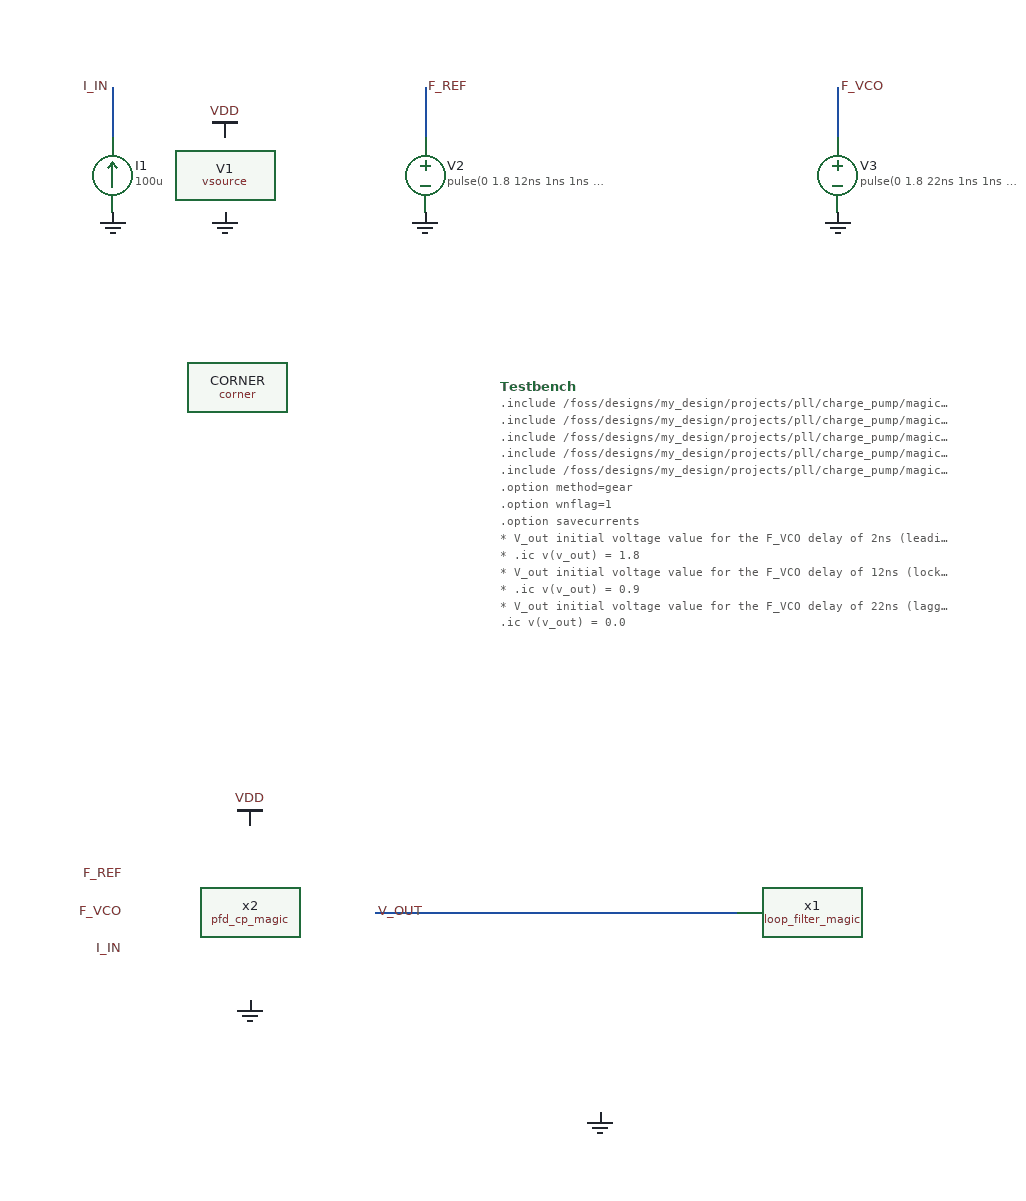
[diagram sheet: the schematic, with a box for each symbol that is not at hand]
v {xschem version=3.4.6 file_version=1.2}
G {}
K {}
V {}
S {}
E {}
B 2 1950 -5830 3310 -5170 {flags=graph
y1=0
y2=1.8
ypos1=0
ypos2=2
divy=5
subdivy=1
unity=1
x1=2.1280357e-07
x2=2.1414051e-07
divx=5
subdivx=1
xlabmag=1.0
ylabmag=1.0


dataset=-1
unitx=1
logx=0
logy=0








linewidth_mult=3







autoload=0
sim_type=tran
color="6 7"
node="f_ref
f_vco"}
B 2 1950 -4440 3330 -3760 {flags=graph
y1=0
y2=0.01
ypos1=0
ypos2=2
divy=5
subdivy=1
unity=1
x1=2.1280357e-07
x2=2.1414051e-07
divx=5
subdivx=1
xlabmag=1.0
ylabmag=1.0


dataset=-1
unitx=1
logx=0
logy=0








linewidth_mult=5





color="6 5"
node="up_pfd_b
down_pfd_b"}
B 2 1950 -5150 3330 -4450 {flags=graph
y1=0.0015141901
y2=0.0079141901
ypos1=0
ypos2=2
divy=5
subdivy=1
unity=1
x1=2.1280357e-07
x2=2.1414051e-07
divx=5
subdivx=1
xlabmag=1.0
ylabmag=1.0


dataset=-1
unitx=1
logx=0
logy=0








linewidth_mult=5

color="6 5"
node="up_pfd
down_pfd"}
B 2 1950 -3740 3330 -3060 {flags=graph
y1=0.002
y2=0.012
ypos1=0
ypos2=2
divy=5
subdivy=1
unity=1
x1=2.1280357e-07
x2=2.1414051e-07
divx=5
subdivx=1
xlabmag=1.0
ylabmag=1.0


dataset=-1
unitx=1
logx=0
logy=0








linewidth_mult=5





color="6 5"
node="up
down_b"}
B 2 1950 -3040 3330 -2360 {flags=graph
y1=0.3664
y2=2.2834
ypos1=0
ypos2=2
divy=5
subdivy=1
unity=1
x1=2.1280357e-07
x2=2.1414051e-07
divx=5
subdivx=1
xlabmag=1.0
ylabmag=1.0


dataset=-1
unitx=1
logx=0
logy=0








linewidth_mult=5





color="6 5"
node="up_b
down"}
B 2 1960 -2320 3340 -1640 {flags=graph
y1=-0.13
y2=1.9
ypos1=0
ypos2=2
divy=5
subdivy=1
unity=1
x1=2.1280357e-07
x2=2.1414051e-07
divx=5
subdivx=1
xlabmag=1.0
ylabmag=1.0


dataset=-1
unitx=1
logx=0
logy=0








linewidth_mult=5





color="6 5"
node="up_input
down_input"}
B 2 400 -4440 1760 -3770 {flags=graph
y1=0.89
y2=0.91
ypos1=0
ypos2=2
divy=5
subdivy=1
unity=1
x1=2.1280357e-07
x2=2.1414051e-07
divx=5
subdivx=1
xlabmag=1.0
ylabmag=1.0


dataset=-1
unitx=1
logx=0
logy=0








linewidth_mult=7






color=5
node=v_out}
B 2 1960 -1540 3320 -870 {flags=graph
y1=3.9e-28
y2=7e-07
ypos1=0
ypos2=2
divy=5
subdivy=1
unity=1
x1=2.1280357e-07
x2=2.1414051e-07
divx=5
subdivx=1
xlabmag=1.0
ylabmag=1.0


dataset=-1
unitx=1
logx=0
logy=0








linewidth_mult=7










color="6 7 6 7 6"
node="i(@m.x2.x5.msky130_fd_pr__nfet_01v8[id])
i(@m.x2.x4.msky130_fd_pr__pfet_01v8[id])
i(@m.x2.x3.msky130_fd_pr__nfet_01v8[id])
i(@m.x2.x2.msky130_fd_pr__pfet_01v8[id])
i(@m.x2.x1.msky130_fd_pr__nfet_01v8[id])"}
B 2 1960 -840 3320 -170 {flags=graph
y1=7.5e-25
y2=1.7e-18
ypos1=0
ypos2=2
divy=5
subdivy=1
unity=1
x1=2.1280357e-07
x2=2.1414051e-07
divx=5
subdivx=1
xlabmag=1.0
ylabmag=1.0


dataset=-1
unitx=1
logx=0
logy=0








linewidth_mult=7










color=6
node=i(@m.x2.x1.msky130_fd_pr__nfet_01v8[id])}
B 2 400 -3740 1760 -3070 {flags=graph
y1=0
y2=0.00032
ypos1=0
ypos2=2
divy=5
subdivy=1
unity=1
x1=2.1280357e-07
x2=2.1414051e-07
divx=5
subdivx=1
xlabmag=1.0
ylabmag=1.0


dataset=-1
unitx=1
logx=0
logy=0








linewidth_mult=7







color="7 7 7 7 7 7 7 7 7 7 7 7 7 7 7 7 7 7 7 7 7 7 7 7 7 7 7 7 7 7 7 7 7 7 7 7 7 7 7 7 7 7 7 7 7 7 7 7 7 7 7 7 7 7 7 7 7 7 7 7 7 7 7 7 7 7 7 7 7 7 7 7 7 7 7 7 7 7 7 7 7 7 7 7 7 7 7 7 7 7 7 7 7 7 7 7 7 7 7 7 7 7 7 7 7 7 7 7 7 7 7 7 7 7 7 7 7 7 7 7 7 7 7 7 7 7 7 7 7 7 7 7 7 7 7 7 7 7 7 7 7 7 7 7"
node="i(@m.x2.x150.msky130_fd_pr__pfet_01v8[id])
i(@m.x2.x149.msky130_fd_pr__nfet_01v8[id])
i(@m.x2.x148.msky130_fd_pr__pfet_01v8[id])
i(@m.x2.x147.msky130_fd_pr__nfet_01v8[id])
i(@m.x2.x146.msky130_fd_pr__pfet_01v8[id])
i(@m.x2.x145.msky130_fd_pr__nfet_01v8[id])
i(@m.x2.x144.msky130_fd_pr__nfet_01v8[id])
i(@m.x2.x143.msky130_fd_pr__nfet_01v8[id])
i(@m.x2.x142.msky130_fd_pr__pfet_01v8[id])
i(@m.x2.x141.msky130_fd_pr__nfet_01v8[id])
i(@m.x2.x140.msky130_fd_pr__pfet_01v8[id])
i(@m.x2.x139.msky130_fd_pr__pfet_01v8[id])
i(@m.x2.x138.msky130_fd_pr__nfet_01v8[id])
i(@m.x2.x136.msky130_fd_pr__pfet_01v8[id])
i(@m.x2.x135.msky130_fd_pr__nfet_01v8[id])
i(@m.x2.x134.msky130_fd_pr__pfet_01v8[id])
i(@m.x2.x133.msky130_fd_pr__nfet_01v8[id])
i(@m.x2.x132.msky130_fd_pr__nfet_01v8[id])
i(@m.x2.x131.msky130_fd_pr__nfet_01v8[id])
i(@m.x2.x130.msky130_fd_pr__pfet_01v8[id])
i(@m.x2.x129.msky130_fd_pr__pfet_01v8[id])
i(@m.x2.x128.msky130_fd_pr__nfet_01v8[id])
i(@m.x2.x127.msky130_fd_pr__pfet_01v8[id])
i(@m.x2.x126.msky130_fd_pr__pfet_01v8[id])
i(@m.x2.x125.msky130_fd_pr__pfet_01v8[id])
i(@m.x2.x124.msky130_fd_pr__nfet_01v8[id])
i(@m.x2.x123.msky130_fd_pr__pfet_01v8[id])
i(@m.x2.x122.msky130_fd_pr__pfet_01v8[id])
i(@m.x2.x121.msky130_fd_pr__pfet_01v8[id])
i(@m.x2.x120.msky130_fd_pr__nfet_01v8[id])
i(@m.x2.x119.msky130_fd_pr__pfet_01v8[id])
i(@m.x2.x118.msky130_fd_pr__pfet_01v8[id])
i(@m.x2.x117.msky130_fd_pr__nfet_01v8[id])
i(@m.x2.x116.msky130_fd_pr__nfet_01v8[id])
i(@m.x2.x115.msky130_fd_pr__nfet_01v8[id])
i(@m.x2.x114.msky130_fd_pr__nfet_01v8[id])
i(@m.x2.x113.msky130_fd_pr__nfet_01v8[id])
i(@m.x2.x112.msky130_fd_pr__pfet_01v8[id])
i(@m.x2.x111.msky130_fd_pr__nfet_01v8[id])
i(@m.x2.x110.msky130_fd_pr__pfet_01v8[id])
i(@m.x2.x108.msky130_fd_pr__pfet_01v8[id])
i(@m.x2.x107.msky130_fd_pr__pfet_01v8[id])
i(@m.x2.x106.msky130_fd_pr__pfet_01v8[id])
i(@m.x2.x105.msky130_fd_pr__nfet_01v8[id])
i(@m.x2.x104.msky130_fd_pr__nfet_01v8[id])
i(@m.x2.x103.msky130_fd_pr__nfet_01v8[id])
i(@m.x2.x102.msky130_fd_pr__pfet_01v8[id])
i(@m.x2.x100.msky130_fd_pr__pfet_01v8[id])
i(@m.x2.x99.msky130_fd_pr__pfet_01v8[id])
i(@m.x2.x97.msky130_fd_pr__nfet_01v8[id])
i(@m.x2.x96.msky130_fd_pr__nfet_01v8[id])
i(@m.x2.x95.msky130_fd_pr__pfet_01v8[id])
i(@m.x2.x94.msky130_fd_pr__pfet_01v8[id])
i(@m.x2.x93.msky130_fd_pr__nfet_01v8[id])
i(@m.x2.x92.msky130_fd_pr__nfet_01v8[id])
i(@m.x2.x91.msky130_fd_pr__nfet_01v8[id])
i(@m.x2.x90.msky130_fd_pr__nfet_01v8[id])
i(@m.x2.x88.msky130_fd_pr__nfet_01v8[id])
i(@m.x2.x87.msky130_fd_pr__nfet_01v8[id])
i(@m.x2.x86.msky130_fd_pr__pfet_01v8[id])
i(@m.x2.x85.msky130_fd_pr__nfet_01v8[id])
i(@m.x2.x84.msky130_fd_pr__pfet_01v8[id])
i(@m.x2.x83.msky130_fd_pr__nfet_01v8[id])
i(@m.x2.x82.msky130_fd_pr__pfet_01v8[id])
i(@m.x2.x81.msky130_fd_pr__nfet_01v8[id])
i(@m.x2.x79.msky130_fd_pr__nfet_01v8[id])
i(@m.x2.x78.msky130_fd_pr__nfet_01v8[id])
i(@m.x2.x77.msky130_fd_pr__nfet_01v8[id])
i(@m.x2.x76.msky130_fd_pr__nfet_01v8[id])
i(@m.x2.x75.msky130_fd_pr__pfet_01v8[id])
i(@m.x2.x74.msky130_fd_pr__nfet_01v8[id])
i(@m.x2.x73.msky130_fd_pr__pfet_01v8[id])
i(@m.x2.x72.msky130_fd_pr__pfet_01v8[id])
i(@m.x2.x71.msky130_fd_pr__pfet_01v8[id])
i(@m.x2.x70.msky130_fd_pr__pfet_01v8[id])
i(@m.x2.x69.msky130_fd_pr__pfet_01v8[id])
i(@m.x2.x68.msky130_fd_pr__nfet_01v8[id])
i(@m.x2.x67.msky130_fd_pr__pfet_01v8[id])
i(@m.x2.x66.msky130_fd_pr__nfet_01v8[id])
i(@m.x2.x65.msky130_fd_pr__pfet_01v8[id])
i(@m.x2.x64.msky130_fd_pr__nfet_01v8[id])
i(@m.x2.x63.msky130_fd_pr__pfet_01v8[id])
i(@m.x2.x62.msky130_fd_pr__pfet_01v8[id])
i(@m.x2.x61.msky130_fd_pr__pfet_01v8[id])
i(@m.x2.x60.msky130_fd_pr__nfet_01v8[id])
i(@m.x2.x59.msky130_fd_pr__pfet_01v8[id])
i(@m.x2.x58.msky130_fd_pr__pfet_01v8[id])
i(@m.x2.x57.msky130_fd_pr__nfet_01v8[id])
i(@m.x2.x56.msky130_fd_pr__nfet_01v8[id])
i(@m.x2.x55.msky130_fd_pr__pfet_01v8[id])
i(@m.x2.x54.msky130_fd_pr__pfet_01v8[id])
i(@m.x2.x53.msky130_fd_pr__pfet_01v8[id])
i(@m.x2.x52.msky130_fd_pr__pfet_01v8[id])
i(@m.x2.x51.msky130_fd_pr__nfet_01v8[id])
i(@m.x2.x50.msky130_fd_pr__pfet_01v8[id])
i(@m.x2.x49.msky130_fd_pr__nfet_01v8[id])
i(@m.x2.x48.msky130_fd_pr__pfet_01v8[id])
i(@m.x2.x47.msky130_fd_pr__nfet_01v8[id])
i(@m.x2.x46.msky130_fd_pr__nfet_01v8[id])
i(@m.x2.x45.msky130_fd_pr__pfet_01v8[id])
i(@m.x2.x44.msky130_fd_pr__pfet_01v8[id])
i(@m.x2.x43.msky130_fd_pr__nfet_01v8[id])
i(@m.x2.x42.msky130_fd_pr__pfet_01v8[id])
i(@m.x2.x41.msky130_fd_pr__pfet_01v8[id])
i(@m.x2.x40.msky130_fd_pr__pfet_01v8[id])
i(@m.x2.x39.msky130_fd_pr__nfet_01v8[id])
i(@m.x2.x38.msky130_fd_pr__nfet_01v8[id])
i(@m.x2.x37.msky130_fd_pr__nfet_01v8[id])
i(@m.x2.x36.msky130_fd_pr__nfet_01v8[id])
i(@m.x2.x35.msky130_fd_pr__nfet_01v8[id])
i(@m.x2.x34.msky130_fd_pr__nfet_01v8[id])
i(@m.x2.x33.msky130_fd_pr__pfet_01v8[id])
i(@m.x2.x32.msky130_fd_pr__pfet_01v8[id])
i(@m.x2.x31.msky130_fd_pr__pfet_01v8[id])
i(@m.x2.x30.msky130_fd_pr__pfet_01v8[id])
i(@m.x2.x29.msky130_fd_pr__nfet_01v8[id])
i(@m.x2.x27.msky130_fd_pr__nfet_01v8[id])
i(@m.x2.x26.msky130_fd_pr__nfet_01v8[id])
i(@m.x2.x25.msky130_fd_pr__pfet_01v8[id])
i(@m.x2.x24.msky130_fd_pr__nfet_01v8[id])
i(@m.x2.x23.msky130_fd_pr__nfet_01v8[id])
i(@m.x2.x22.msky130_fd_pr__pfet_01v8[id])
i(@m.x2.x21.msky130_fd_pr__pfet_01v8[id])
i(@m.x2.x20.msky130_fd_pr__nfet_01v8[id])
i(@m.x2.x19.msky130_fd_pr__nfet_01v8[id])
i(@m.x2.x18.msky130_fd_pr__nfet_01v8[id])
i(@m.x2.x17.msky130_fd_pr__pfet_01v8[id])
i(@m.x2.x16.msky130_fd_pr__nfet_01v8[id])
i(@m.x2.x15.msky130_fd_pr__nfet_01v8[id])
i(@m.x2.x14.msky130_fd_pr__nfet_01v8[id])
i(@m.x2.x13.msky130_fd_pr__pfet_01v8[id])
i(@m.x2.x12.msky130_fd_pr__pfet_01v8[id])
i(@m.x2.x11.msky130_fd_pr__pfet_01v8[id])
i(@m.x2.x10.msky130_fd_pr__pfet_01v8[id])
i(@m.x2.x9.msky130_fd_pr__pfet_01v8[id])
i(@m.x2.x8.msky130_fd_pr__pfet_01v8[id])
i(@m.x2.x7.msky130_fd_pr__nfet_01v8[id])
i(@m.x2.x6.msky130_fd_pr__pfet_01v8[id])
i(@m.x2.x5.msky130_fd_pr__nfet_01v8[id])
i(@m.x2.x4.msky130_fd_pr__nfet_01v8[id])
i(@m.x2.x3.msky130_fd_pr__nfet_01v8[id])
i(@m.x2.x2.msky130_fd_pr__pfet_01v8[id])
i(@m.x2.x1.msky130_fd_pr__pfet_01v8[id])
i(@m.x2.x0.msky130_fd_pr__nfet_01v8[id])"}
B 2 400 -3010 1760 -2340 {flags=graph
y1=3.4e-18
y2=0.00012
ypos1=0
ypos2=2
divy=5
subdivy=1
unity=1
x1=2.1280357e-07
x2=2.1414051e-07
divx=5
subdivx=1
xlabmag=1.0
ylabmag=1.0


dataset=-1
unitx=1
logx=0
logy=0








linewidth_mult=5








color=6
node="\\"i(@m.x2.x10.msky130_fd_pr__pfet_01v8[id]) i(@m.x2.x73.msky130_fd_pr__pfet_01v8[id]) i(@m.x2.x130.msky130_fd_pr__pfet_01v8[id]) i(@m.x2.x146.msky130_fd_pr__pfet_01v8[id]) + + + \\""}
B 2 400 -2280 1760 -1610 {flags=graph
y1=1.2e-14
y2=0.00012
ypos1=0
ypos2=2
divy=5
subdivy=1
unity=1
x1=2.1280357e-07
x2=2.1414051e-07
divx=5
subdivx=1
xlabmag=1.0
ylabmag=1.0


dataset=-1
unitx=1
logx=0
logy=0








linewidth_mult=4








color=7
node="\\"i(@m.x2.x76.msky130_fd_pr__nfet_01v8[id]) i(@m.x2.x105.msky130_fd_pr__nfet_01v8[id]) + \\""}
B 2 400 -1570 1760 -900 {flags=graph
y1=3.5e-18
y2=0.00012
ypos1=0
ypos2=2
divy=5
subdivy=1
unity=1
x1=2.1280357e-07
x2=2.1414051e-07
divx=5
subdivx=1
xlabmag=1.0
ylabmag=1.0


dataset=-1
unitx=1
logx=0
logy=0








linewidth_mult=5








color="6 7"
node="\\"i(@m.x2.x10.msky130_fd_pr__pfet_01v8[id]) i(@m.x2.x73.msky130_fd_pr__pfet_01v8[id]) i(@m.x2.x130.msky130_fd_pr__pfet_01v8[id]) i(@m.x2.x146.msky130_fd_pr__pfet_01v8[id]) + + + \\"
\\"i(@m.x2.x76.msky130_fd_pr__nfet_01v8[id]) i(@m.x2.x105.msky130_fd_pr__nfet_01v8[id]) + \\""}
N 1040 -5570 1040 -5530 {
lab=F_REF}
N 1370 -5570 1370 -5530 {
lab=F_VCO}
N 790 -5570 790 -5530 {
lab=I_IN}
N 1000 -4910 1290 -4910 {lab=V_OUT}
C {sky130_fd_pr/corner.sym} 890 -5330 0 0 {name=CORNER only_toplevel=false corner=tt}
C {devices/code.sym} 1100 -5331.25 0 0 {name=Testbench only_toplevel=false value="

.include /foss/designs/my_design/projects/pll/charge_pump/magic/pfd_cp_magic.spice
.include /foss/designs/my_design/projects/pll/charge_pump/magic/pfd_cp_input_magic.spice
.include /foss/designs/my_design/projects/pll/charge_pump/magic/charge_pump_magic.spice
.include /foss/designs/my_design/projects/pll/charge_pump/magic/rail_to_rail_opamp_magic.spice
.include /foss/designs/my_design/projects/pll/charge_pump/magic/loop_filter_magic.spice

.option method=gear
.option wnflag=1
.option savecurrents

* V_out initial voltage value for the F_VCO delay of 2ns  (leading)
* .ic v(v_out) = 1.8

* V_out initial voltage value for the F_VCO delay of 12ns (lock condition)
* .ic v(v_out) = 0.9

* V_out initial voltage value for the F_VCO delay of 22ns (lagging)
.ic v(v_out) = 0.0

.control
  save v(f_ref) save v(f_vco) save v(i_in) save v(up_pfd) v(down_pfd) v(up_pfd_b) v(down_pfd_b) v(up) v(up_b) v(down) v(down_b) v(x) v(opamp_out) v(up_input) v(down_input) v(down_gate) v(v_out)
  * save all

  * timestep for exact simulation results
  * tran 5ps 0.5us

  * timestep for faster simulation results
  tran 50ps 0.5us

  remzerovec
  write pfd_charge_pump_magic_3.raw
  set appendwrite

.endc

"
}
C {devices/vsource.sym} 880 -5500 0 0 {name=V1 value=1.8 savecurrent=false}
C {devices/gnd.sym} 880 -5470 0 0 {name=l2 lab=GND}
C {devices/vdd.sym} 880 -5530 0 1 {name=l3 lab=VDD}
C {devices/vsource.sym} 1040 -5500 0 0 {name=V2 value=pulse"(0 1.8 12ns 1ns 1ns 24ns 50ns)" savecurrent=false
* }
C {devices/gnd.sym} 1040 -5470 0 0 {name=l10 lab=GND}
C {devices/lab_pin.sym} 1040 -5570 0 1 {name=p11 sig_type=std_logic lab=F_REF}
C {devices/vsource.sym} 1370 -5500 0 0 {name=V3 value="pulse(0 1.8 22ns 1ns 1ns 24ns 50ns)" savecurrent=false}
C {devices/gnd.sym} 1370 -5470 0 0 {name=l15 lab=GND}
C {devices/lab_pin.sym} 1370 -5570 0 1 {name=p12 sig_type=std_logic lab=F_VCO}
C {devices/isource.sym} 790 -5500 2 0 {name=I1 value=100u}
C {devices/gnd.sym} 790 -5470 0 0 {name=l26 lab=GND}
C {devices/lab_pin.sym} 790 -5570 2 1 {name=p3 sig_type=std_logic lab=I_IN}
C {devices/vdd.sym} 900 -4980 0 1 {name=l32 lab=VDD
value="

.include /foss/pdks/sky130A/libs.ref/sky130_fd_sc_hd/spice/sky130_fd_sc_hd.spice

.option method=gear
.option wnflag=1

* V_out initial voltage value for the F_VCO delay of 2ns  (leading)
* .ic v(vout) = 1.8

* V_out initial voltage value for the F_VCO delay of 12ns (lock condition)
.ic v(vout) = 0.83

* V_out initial voltage value for the F_VCO delay of 22ns (lagging)
* .ic v(vout) = 0

.control
  save v(f_ref) save v(f_vco) save v(i_in) save v(up_pfd) v(down_pfd) v(up_pfd_b) v(down_pfd_b) v(up) v(up_b) v(down) v(down_b) v(x) v(opamp_out) v(up_input) v(down_input) v(down_gate) v(vout)

  * timestep for exact simulation results
  * tran 5ps 0.5us

  * timestep for faster simulation results
  tran 50ps 0.5us

  remzerovec
  write pfd_charge_pump_10.raw
  set appendwrite

.endc

"


v(vout)="0.0

.control
  save all

  * timestep for exact simulation results
  tran 5ps 0.5us

  * timestep for faster simulation results
  * tran 50ps 0.5us

  remzerovec
  write pfd_charge_pump_10.raw
  set appendA}
C {devices/gnd.sym} 900 -4840 0 0 {name=l33 lab=GND
value="

.include /foss/pdks/sky130A/libs.ref/sky130_fd_sc_hd/spice/sky130_fd_sc_hd.spice

.option method=gear
.option wnflag=1

* V_out initial voltage value for the F_VCO delay of 2ns  (leading)
* .ic v(vout) = 1.8

* V_out initial voltage value for the F_VCO delay of 12ns (lock condition)
.ic v(vout) = 0.83

* V_out initial voltage value for the F_VCO delay of 22ns (lagging)
* .ic v(vout) = 0

.control
  save v(f_ref) save v(f_vco) save v(i_in) save v(up_pfd) v(down_pfd) v(up_pfd_b) v(down_pfd_b) v(up) v(up_b) v(down) v(down_b) v(x) v(opamp_out) v(up_input) v(down_input) v(down_gate) v(vout)

  * timestep for exact simulation results
  * tran 5ps 0.5us

  * timestep for faster simulation results
  tran 50ps 0.5us

  remzerovec
  write pfd_charge_pump_10.raw
  set appendwrite

.endc

"}
C {devices/gnd.sym} 1180 -4750 0 0 {name=l1 lab=GND
value="

.include /foss/pdks/sky130A/libs.ref/sky130_fd_sc_hd/spice/sky130_fd_sc_hd.spice

.option method=gear
.option wnflag=1

* V_out initial voltage value for the F_VCO delay of 2ns  (leading)
* .ic v(vout) = 1.8

* V_out initial voltage value for the F_VCO delay of 12ns (lock condition)
.ic v(vout) = 0.83

* V_out initial voltage value for the F_VCO delay of 22ns (lagging)
* .ic v(vout) = 0

.control
  save v(f_ref) save v(f_vco) save v(i_in) save v(up_pfd) v(down_pfd) v(up_pfd_b) v(down_pfd_b) v(up) v(up_b) v(down) v(down_b) v(x) v(opamp_out) v(up_input) v(down_input) v(down_gate) v(vout)

  * timestep for exact simulation results
  * tran 5ps 0.5us

  * timestep for faster simulation results
  tran 50ps 0.5us

  remzerovec
  write pfd_charge_pump_10.raw
  set appendwrite

.endc

"}
C {loop_filter_magic.sym} 1180 -4830 0 0 {name=x1}
C {lab_pin.sym} 1000 -4910 0 1 {name=p1 lab=V_OUT}
C {lab_pin.sym} 800 -4940 0 0 {name=p5 lab=F_REF}
C {lab_pin.sym} 800 -4910 0 0 {name=p6 lab=F_VCO}
C {lab_pin.sym} 800 -4880 0 0 {name=p7 lab=I_IN}
C {pfd_cp_magic.sym} 900 -4910 0 0 {name=x2}
